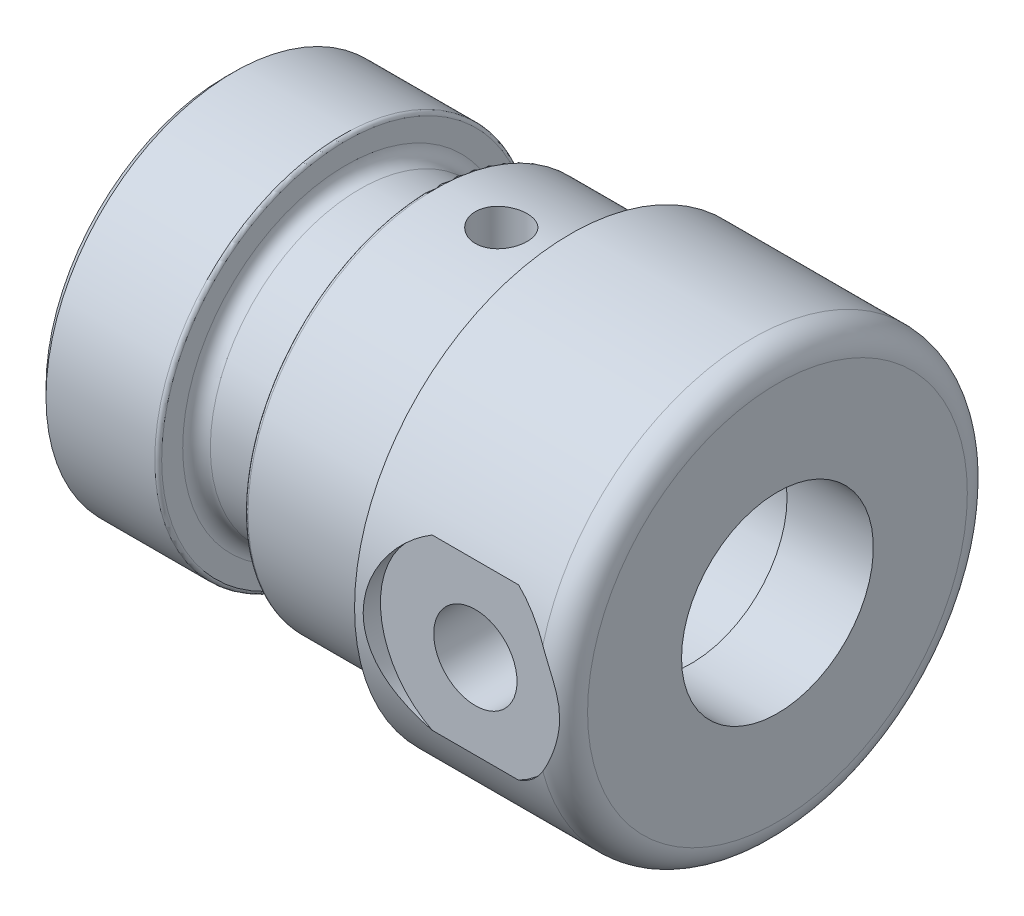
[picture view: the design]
ISO-10303-21;
HEADER;
FILE_DESCRIPTION(('STEP AP214'),'2;1');
FILE_NAME('part.step','',(''),(''),'','','');
FILE_SCHEMA(('AUTOMOTIVE_DESIGN { 1 0 10303 214 1 1 1 1 }'));
ENDSEC;
DATA;
#1=APPLICATION_CONTEXT('core data for automotive mechanical design processes');
#2=APPLICATION_PROTOCOL_DEFINITION('international standard','automotive_design',2000,#1);
#3=PRODUCT_CONTEXT('',#1,'mechanical');
#4=PRODUCT('Part','Part','',(#3));
#5=PRODUCT_RELATED_PRODUCT_CATEGORY('part','',(#4));
#6=PRODUCT_DEFINITION_FORMATION('','',#4);
#7=PRODUCT_DEFINITION_CONTEXT('part definition',#1,'design');
#8=PRODUCT_DEFINITION('design','',#6,#7);
#9=PRODUCT_DEFINITION_SHAPE('','',#8);
#10=(LENGTH_UNIT() NAMED_UNIT(*) SI_UNIT(.MILLI.,.METRE.));
#11=(NAMED_UNIT(*) PLANE_ANGLE_UNIT() SI_UNIT($,.RADIAN.));
#12=(NAMED_UNIT(*) SI_UNIT($,.STERADIAN.) SOLID_ANGLE_UNIT());
#13=UNCERTAINTY_MEASURE_WITH_UNIT(LENGTH_MEASURE(1.E-05),#10,'distance_accuracy_value','');
#14=(GEOMETRIC_REPRESENTATION_CONTEXT(3) GLOBAL_UNCERTAINTY_ASSIGNED_CONTEXT((#13)) GLOBAL_UNIT_ASSIGNED_CONTEXT((#10,
#11,#12)) REPRESENTATION_CONTEXT('',''));
#15=CARTESIAN_POINT('',(0.,0.,0.));
#16=DIRECTION('',(0.,0.,1.));
#17=DIRECTION('',(1.,0.,0.));
#18=AXIS2_PLACEMENT_3D('',#15,#16,#17);
#19=CARTESIAN_POINT('',(0.,0.,0.));
#20=DIRECTION('',(-1.,0.,0.));
#21=DIRECTION('',(0.,0.,1.));
#22=AXIS2_PLACEMENT_3D('',#19,#20,#21);
#23=CYLINDRICAL_SURFACE('',#22,5.55625);
#24=CARTESIAN_POINT('',(32.,0.,0.));
#25=DIRECTION('',(-1.,0.,0.));
#26=DIRECTION('',(0.,0.,1.));
#27=AXIS2_PLACEMENT_3D('',#24,#25,#26);
#28=CIRCLE('',#27,5.55625);
#29=CARTESIAN_POINT('',(32.,0.,5.55624999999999));
#30=VERTEX_POINT('',#29);
#31=EDGE_CURVE('E190',#30,#30,#28,.T.);
#32=ORIENTED_EDGE('',*,*,#31,.F.);
#33=EDGE_LOOP('',(#32));
#34=FACE_BOUND('',#33,.T.);
#35=CARTESIAN_POINT('',(27.0000000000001,0.,0.));
#36=DIRECTION('',(-1.,0.,0.));
#37=DIRECTION('',(0.,0.,1.));
#38=AXIS2_PLACEMENT_3D('',#35,#36,#37);
#39=CIRCLE('',#38,5.55625);
#40=CARTESIAN_POINT('',(27.,-2.19603483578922,5.10385590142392));
#41=VERTEX_POINT('',#40);
#42=CARTESIAN_POINT('',(27.,2.19603483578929,5.10385590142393));
#43=VERTEX_POINT('',#42);
#44=EDGE_CURVE('E109',#41,#43,#39,.F.);
#45=ORIENTED_EDGE('',*,*,#44,.F.);
#46=CARTESIAN_POINT('',(28.4130000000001,0.,5.55625000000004));
#47=CARTESIAN_POINT('',(28.4129937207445,0.128763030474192,5.55624497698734));
#48=CARTESIAN_POINT('',(28.4026322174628,0.257738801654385,5.5517233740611));
#49=CARTESIAN_POINT('',(28.3615871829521,0.511994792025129,5.53408587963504));
#50=CARTESIAN_POINT('',(28.3308532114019,0.637265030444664,5.52094865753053));
#51=CARTESIAN_POINT('',(28.2504225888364,0.880031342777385,5.48747848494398));
#52=CARTESIAN_POINT('',(28.2007923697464,0.997552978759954,5.46717076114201));
#53=CARTESIAN_POINT('',(28.0842672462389,1.22247857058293,5.42131472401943));
#54=CARTESIAN_POINT('',(28.0173767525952,1.32988510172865,5.3957677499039));
#55=CARTESIAN_POINT('',(27.8644530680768,1.53746754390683,5.34043137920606));
#56=CARTESIAN_POINT('',(27.7776425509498,1.63703135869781,5.31049545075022));
#57=CARTESIAN_POINT('',(27.5889907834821,1.82072166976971,5.25035680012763));
#58=CARTESIAN_POINT('',(27.4871410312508,1.90483937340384,5.22015393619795));
#59=CARTESIAN_POINT('',(27.2645849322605,2.05979566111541,5.16104762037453));
#60=CARTESIAN_POINT('',(27.1431533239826,2.12966040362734,5.13230475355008));
#61=CARTESIAN_POINT('',(26.8888396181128,2.24769961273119,5.08172361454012));
#62=CARTESIAN_POINT('',(26.7559639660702,2.29588619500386,5.05988148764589));
#63=CARTESIAN_POINT('',(26.4895779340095,2.36661894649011,5.02717478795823));
#64=CARTESIAN_POINT('',(26.3564459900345,2.3903481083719,5.01580689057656));
#65=CARTESIAN_POINT('',(26.08764245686,2.41517595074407,5.00390342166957));
#66=CARTESIAN_POINT('',(25.9519725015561,2.41628872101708,5.00336110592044));
#67=CARTESIAN_POINT('',(25.6942201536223,2.39673762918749,5.01274790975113));
#68=CARTESIAN_POINT('',(25.571959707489,2.37790912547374,5.02179453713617));
#69=CARTESIAN_POINT('',(25.3325453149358,2.32210861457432,5.04783750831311));
#70=CARTESIAN_POINT('',(25.2153924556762,2.28513276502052,5.06483553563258));
#71=CARTESIAN_POINT('',(24.9864363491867,2.19335626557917,5.10525751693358));
#72=CARTESIAN_POINT('',(24.8748081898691,2.13818029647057,5.12881498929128));
#73=CARTESIAN_POINT('',(24.66193674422,2.01183783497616,5.17967693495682));
#74=CARTESIAN_POINT('',(24.5606977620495,1.94066475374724,5.20698295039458));
#75=CARTESIAN_POINT('',(24.3616140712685,1.77662469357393,5.26533637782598));
#76=CARTESIAN_POINT('',(24.26495098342,1.68235945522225,5.29649614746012));
#77=CARTESIAN_POINT('',(24.0883890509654,1.47867630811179,5.35693096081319));
#78=CARTESIAN_POINT('',(24.0084948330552,1.36925423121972,5.38620548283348));
#79=CARTESIAN_POINT('',(23.8657972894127,1.13450757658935,5.44055960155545));
#80=CARTESIAN_POINT('',(23.8035144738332,1.00883302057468,5.4655043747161));
#81=CARTESIAN_POINT('',(23.7013970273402,0.747428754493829,5.50733486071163));
#82=CARTESIAN_POINT('',(23.6615488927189,0.611705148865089,5.52422542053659));
#83=CARTESIAN_POINT('',(23.6079972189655,0.343895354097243,5.54711464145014));
#84=CARTESIAN_POINT('',(23.592710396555,0.212182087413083,5.55377158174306));
#85=CARTESIAN_POINT('',(23.5839457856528,-0.0520870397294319,5.55757513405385));
#86=CARTESIAN_POINT('',(23.5904610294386,-0.184642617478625,5.55472478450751));
#87=CARTESIAN_POINT('',(23.6240187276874,-0.439154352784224,5.54025525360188));
#88=CARTESIAN_POINT('',(23.6499144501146,-0.561292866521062,5.52912613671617));
#89=CARTESIAN_POINT('',(23.7198626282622,-0.799336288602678,5.49976068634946));
#90=CARTESIAN_POINT('',(23.7639173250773,-0.915240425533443,5.48152347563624));
#91=CARTESIAN_POINT('',(23.8703548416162,-1.14162895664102,5.43895992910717));
#92=CARTESIAN_POINT('',(23.9332673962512,-1.25183079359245,5.41446111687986));
#93=CARTESIAN_POINT('',(24.0750564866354,-1.46051096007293,5.36194173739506));
#94=CARTESIAN_POINT('',(24.1539398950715,-1.55898421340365,5.33391965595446));
#95=CARTESIAN_POINT('',(24.332542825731,-1.74942418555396,5.27466863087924));
#96=CARTESIAN_POINT('',(24.4334012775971,-1.84030042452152,5.24335919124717));
#97=CARTESIAN_POINT('',(24.6493676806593,-2.00418121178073,5.1829353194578));
#98=CARTESIAN_POINT('',(24.7644799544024,-2.0771803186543,5.15382155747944));
#99=CARTESIAN_POINT('',(25.0088419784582,-2.20443007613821,5.10071262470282));
#100=CARTESIAN_POINT('',(25.1383271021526,-2.25827957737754,5.07683059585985));
#101=CARTESIAN_POINT('',(25.4058996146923,-2.34291594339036,5.03833900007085));
#102=CARTESIAN_POINT('',(25.5439789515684,-2.3737240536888,5.0237208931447));
#103=CARTESIAN_POINT('',(25.8126214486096,-2.40920871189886,5.00679323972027));
#104=CARTESIAN_POINT('',(25.9428721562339,-2.41582135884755,5.00357246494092));
#105=CARTESIAN_POINT('',(26.2025732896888,-2.40798643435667,5.00734830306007));
#106=CARTESIAN_POINT('',(26.3320238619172,-2.39354283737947,5.01434298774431));
#107=CARTESIAN_POINT('',(26.5790889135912,-2.34567625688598,5.03689892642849));
#108=CARTESIAN_POINT('',(26.6969630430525,-2.31333865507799,5.05196884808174));
#109=CARTESIAN_POINT('',(26.9256144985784,-2.23171559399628,5.08855076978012));
#110=CARTESIAN_POINT('',(27.0363897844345,-2.18242528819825,5.11006461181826));
#111=CARTESIAN_POINT('',(27.2553056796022,-2.06474617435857,5.15878167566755));
#112=CARTESIAN_POINT('',(27.3628443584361,-1.99535269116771,5.1862572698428));
#113=CARTESIAN_POINT('',(27.5653540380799,-1.84078210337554,5.24311117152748));
#114=CARTESIAN_POINT('',(27.6603200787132,-1.75559880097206,5.27249022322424));
#115=CARTESIAN_POINT('',(27.8430151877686,-1.56359151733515,5.33272975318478));
#116=CARTESIAN_POINT('',(27.9295138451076,-1.4555663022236,5.36351439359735));
#117=CARTESIAN_POINT('',(28.0832591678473,-1.22546498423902,5.42072074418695));
#118=CARTESIAN_POINT('',(28.1504970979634,-1.10338254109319,5.44714047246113));
#119=CARTESIAN_POINT('',(28.2625562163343,-0.849881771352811,5.49234854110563));
#120=CARTESIAN_POINT('',(28.3076675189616,-0.718611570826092,5.51123500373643));
#121=CARTESIAN_POINT('',(28.3579868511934,-0.516991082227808,5.53256145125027));
#122=CARTESIAN_POINT('',(28.3718643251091,-0.449057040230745,5.53850101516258));
#123=CARTESIAN_POINT('',(28.3937338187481,-0.31209363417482,5.547900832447));
#124=CARTESIAN_POINT('',(28.4017300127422,-0.243065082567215,5.55136284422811));
#125=CARTESIAN_POINT('',(28.4088204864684,-0.144894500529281,5.55443594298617));
#126=CARTESIAN_POINT('',(28.4103869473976,-0.115942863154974,5.55511550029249));
#127=CARTESIAN_POINT('',(28.4124774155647,-0.0579977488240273,5.55602309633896));
#128=CARTESIAN_POINT('',(28.4130014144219,-0.0290042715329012,5.55625113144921));
#129=CARTESIAN_POINT('',(28.4130000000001,0.,5.55625000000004));
#130=B_SPLINE_CURVE_WITH_KNOTS('',3,(#46,#47,#48,#49,#50,#51,#52,#53,#54,#55,#56,#57,#58,#59,
#60,#61,#62,#63,#64,#65,#66,#67,#68,#69,#70,#71,#72,#73,#74,#75,#76,#77,#78,#79,#80,#81,#82,#83,
#84,#85,#86,#87,#88,#89,#90,#91,#92,#93,#94,#95,#96,#97,#98,#99,#100,#101,#102,#103,#104,#105,
#106,#107,#108,#109,#110,#111,#112,#113,#114,#115,#116,#117,#118,#119,#120,#121,#122,#123,#124,
#125,#126,#127,#128,#129),.UNSPECIFIED.,.T.,.F.,(4,2,2,2,2,2,2,2,2,2,2,2,2,2,2,2,2,2,2,2,2,2,2,
2,2,2,2,2,2,2,2,2,2,2,2,2,2,2,2,2,2,4),(0.,0.386175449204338,0.773310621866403,1.15909715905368,
1.5447852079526,1.94937007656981,2.3541845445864,2.78106643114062,3.20770944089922,
3.61257996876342,4.0171982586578,4.38756673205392,4.75801365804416,5.13663488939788,
5.5154123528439,5.92925111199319,6.34320390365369,6.7683491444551,7.19323821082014,
7.58944560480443,7.98552638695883,8.35985951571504,8.73423885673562,9.1203176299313,
9.5065628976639,9.92264925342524,10.3388621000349,10.7633411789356,11.1874283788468,
11.5767310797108,11.9659603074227,12.3338231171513,12.7017911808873,13.0928585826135,
13.4840798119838,13.9073542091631,14.3308202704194,14.7485748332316,14.9571043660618,
15.1654857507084,15.2524722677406,15.3394594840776),.UNSPECIFIED.);
#131=EDGE_CURVE('E160',#41,#43,#130,.T.);
#132=ORIENTED_EDGE('',*,*,#131,.T.);
#133=EDGE_LOOP('',(#45,#132));
#134=FACE_BOUND('',#133,.T.);
#135=ADVANCED_FACE('F44',(#34,#134),#23,.F.);
#136=CARTESIAN_POINT('',(0.,0.,0.));
#137=DIRECTION('',(-1.,0.,0.));
#138=DIRECTION('',(0.,0.,1.));
#139=AXIS2_PLACEMENT_3D('',#136,#137,#138);
#140=CYLINDRICAL_SURFACE('',#139,10.875);
#141=CARTESIAN_POINT('',(6.80000000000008,0.,0.));
#142=DIRECTION('',(-1.,0.,0.));
#143=DIRECTION('',(0.,0.,1.));
#144=AXIS2_PLACEMENT_3D('',#141,#142,#143);
#145=CIRCLE('',#144,10.875);
#146=CARTESIAN_POINT('',(6.80000000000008,0.,10.875));
#147=VERTEX_POINT('',#146);
#148=EDGE_CURVE('E258',#147,#147,#145,.T.);
#149=ORIENTED_EDGE('',*,*,#148,.T.);
#150=EDGE_LOOP('',(#149));
#151=FACE_BOUND('',#150,.T.);
#152=CARTESIAN_POINT('',(0.500000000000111,0.,0.));
#153=DIRECTION('',(1.,0.,0.));
#154=DIRECTION('',(0.,0.,-1.));
#155=AXIS2_PLACEMENT_3D('',#152,#153,#154);
#156=CIRCLE('',#155,10.875);
#157=CARTESIAN_POINT('',(0.500000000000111,0.,-10.875));
#158=VERTEX_POINT('',#157);
#159=EDGE_CURVE('E189',#158,#158,#156,.T.);
#160=ORIENTED_EDGE('',*,*,#159,.T.);
#161=EDGE_LOOP('',(#160));
#162=FACE_BOUND('',#161,.T.);
#163=ADVANCED_FACE('F46',(#151,#162),#140,.T.);
#164=CARTESIAN_POINT('',(0.,5.55624999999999,0.));
#165=DIRECTION('',(1.,0.,0.));
#166=DIRECTION('',(0.,0.,-1.));
#167=AXIS2_PLACEMENT_3D('',#164,#165,#166);
#168=PLANE('',#167);
#169=CARTESIAN_POINT('',(0.,0.,0.));
#170=DIRECTION('',(-1.,0.,0.));
#171=DIRECTION('',(0.,0.,1.));
#172=AXIS2_PLACEMENT_3D('',#169,#170,#171);
#173=CIRCLE('',#172,6.);
#174=CARTESIAN_POINT('',(0.,0.,6.00000000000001));
#175=VERTEX_POINT('',#174);
#176=EDGE_CURVE('E113',#175,#175,#173,.T.);
#177=ORIENTED_EDGE('',*,*,#176,.F.);
#178=EDGE_LOOP('',(#177));
#179=FACE_BOUND('',#178,.T.);
#180=CARTESIAN_POINT('',(0.,0.,0.));
#181=DIRECTION('',(1.,0.,0.));
#182=DIRECTION('',(0.,0.,-1.));
#183=AXIS2_PLACEMENT_3D('',#180,#181,#182);
#184=CIRCLE('',#183,10.375);
#185=CARTESIAN_POINT('',(0.,0.,-10.375));
#186=VERTEX_POINT('',#185);
#187=EDGE_CURVE('E187',#186,#186,#184,.F.);
#188=ORIENTED_EDGE('',*,*,#187,.T.);
#189=EDGE_LOOP('',(#188));
#190=FACE_BOUND('',#189,.T.);
#191=ADVANCED_FACE('F173',(#179,#190),#168,.F.);
#192=CARTESIAN_POINT('',(32.,12.5,0.));
#193=DIRECTION('',(-1.,0.,0.));
#194=DIRECTION('',(0.,0.,1.));
#195=AXIS2_PLACEMENT_3D('',#192,#193,#194);
#196=PLANE('',#195);
#197=CARTESIAN_POINT('',(32.,0.,0.));
#198=DIRECTION('',(-1.,0.,0.));
#199=DIRECTION('',(0.,0.,1.));
#200=AXIS2_PLACEMENT_3D('',#197,#198,#199);
#201=CIRCLE('',#200,11.);
#202=CARTESIAN_POINT('',(32.,0.,11.));
#203=VERTEX_POINT('',#202);
#204=EDGE_CURVE('E345',#203,#203,#201,.F.);
#205=ORIENTED_EDGE('',*,*,#204,.T.);
#206=EDGE_LOOP('',(#205));
#207=FACE_BOUND('',#206,.T.);
#208=ORIENTED_EDGE('',*,*,#31,.T.);
#209=EDGE_LOOP('',(#208));
#210=FACE_BOUND('',#209,.T.);
#211=ADVANCED_FACE('F171',(#207,#210),#196,.F.);
#212=CARTESIAN_POINT('',(0.,0.,0.));
#213=DIRECTION('',(-1.,0.,0.));
#214=DIRECTION('',(0.,0.,1.));
#215=AXIS2_PLACEMENT_3D('',#212,#213,#214);
#216=CYLINDRICAL_SURFACE('',#215,12.5);
#217=DIRECTION('',(-1.,0.,0.));
#218=VECTOR('',#217,1.);
#219=CARTESIAN_POINT('',(0.,4.89897948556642,11.5));
#220=LINE('',#219,#218);
#221=CARTESIAN_POINT('',(28.5,4.8989794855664,11.5));
#222=VERTEX_POINT('',#221);
#223=CARTESIAN_POINT('',(23.5,4.89897948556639,11.5));
#224=VERTEX_POINT('',#223);
#225=EDGE_CURVE('E11',#222,#224,#220,.T.);
#226=ORIENTED_EDGE('',*,*,#225,.F.);
#227=CARTESIAN_POINT('',(28.5,4.8989794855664,11.5));
#228=CARTESIAN_POINT('',(28.6410710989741,4.82698356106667,11.5306652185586));
#229=CARTESIAN_POINT('',(28.7786535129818,4.74909801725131,11.5630505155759));
#230=CARTESIAN_POINT('',(29.0461685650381,4.58211025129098,11.6302362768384));
#231=CARTESIAN_POINT('',(29.1761030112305,4.4930106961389,11.6650361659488));
#232=CARTESIAN_POINT('',(29.5535613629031,4.20965109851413,11.7715548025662));
#233=CARTESIAN_POINT('',(29.7886985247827,3.99935156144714,11.8453829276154));
#234=CARTESIAN_POINT('',(30.220047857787,3.54120421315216,11.9903049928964));
#235=CARTESIAN_POINT('',(30.4162636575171,3.29335990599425,12.0613991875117));
#236=CARTESIAN_POINT('',(30.6772407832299,2.89800310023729,12.1601870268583));
#237=CARTESIAN_POINT('',(30.7586944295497,2.76224240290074,12.1918155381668));
#238=CARTESIAN_POINT('',(30.9098543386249,2.48362880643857,12.25160556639));
#239=CARTESIAN_POINT('',(30.9795656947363,2.34077901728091,12.2797685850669));
#240=CARTESIAN_POINT('',(31.1055663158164,2.05127274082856,12.3314054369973));
#241=CARTESIAN_POINT('',(31.1620535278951,1.90471451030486,12.3549474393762));
#242=CARTESIAN_POINT('',(31.2624238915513,1.60673398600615,12.3972187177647));
#243=CARTESIAN_POINT('',(31.3063128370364,1.45531396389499,12.4159502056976));
#244=CARTESIAN_POINT('',(31.3810098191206,1.14874718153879,12.4480572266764));
#245=CARTESIAN_POINT('',(31.4118200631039,0.993601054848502,12.4614336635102));
#246=CARTESIAN_POINT('',(31.4599877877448,0.680852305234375,12.4824274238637));
#247=CARTESIAN_POINT('',(31.4773463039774,0.523249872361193,12.4900451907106));
#248=CARTESIAN_POINT('',(31.497551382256,0.219568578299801,12.4989199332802));
#249=CARTESIAN_POINT('',(31.5014436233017,0.0735716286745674,12.5006351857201));
#250=CARTESIAN_POINT('',(31.4976043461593,-0.218291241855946,12.4989459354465));
#251=CARTESIAN_POINT('',(31.4898689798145,-0.364157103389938,12.495539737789));
#252=CARTESIAN_POINT('',(31.4628604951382,-0.654526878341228,12.483697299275));
#253=CARTESIAN_POINT('',(31.4435936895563,-0.799031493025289,12.4752638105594));
#254=CARTESIAN_POINT('',(31.393729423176,-1.08575702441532,12.4535863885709));
#255=CARTESIAN_POINT('',(31.3631276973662,-1.22797706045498,12.4403406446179));
#256=CARTESIAN_POINT('',(31.2918014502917,-1.50560997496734,12.4097602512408));
#257=CARTESIAN_POINT('',(31.2513465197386,-1.64110420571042,12.3925350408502));
#258=CARTESIAN_POINT('',(31.1603319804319,-1.90811413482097,12.3542435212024));
#259=CARTESIAN_POINT('',(31.1097687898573,-2.03962840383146,12.3331758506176));
#260=CARTESIAN_POINT('',(30.9435171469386,-2.42703027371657,12.2649118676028));
#261=CARTESIAN_POINT('',(30.8132260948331,-2.6759331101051,12.212636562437));
#262=CARTESIAN_POINT('',(30.5086536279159,-3.1638324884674,12.0957442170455));
#263=CARTESIAN_POINT('',(30.3321872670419,-3.40131804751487,12.0305717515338));
#264=CARTESIAN_POINT('',(29.9442517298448,-3.84440880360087,11.896388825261));
#265=CARTESIAN_POINT('',(29.732795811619,-4.05002601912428,11.8273798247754));
#266=CARTESIAN_POINT('',(29.3515425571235,-4.3654866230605,11.713713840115));
#267=CARTESIAN_POINT('',(29.189868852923,-4.48499785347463,11.6682888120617));
#268=CARTESIAN_POINT('',(28.8540056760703,-4.70584437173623,11.5809782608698));
#269=CARTESIAN_POINT('',(28.679833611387,-4.80720427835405,11.5390879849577));
#270=CARTESIAN_POINT('',(28.5,-4.89897948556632,11.5));
#271=B_SPLINE_CURVE_WITH_KNOTS('',3,(#227,#228,#229,#230,#231,#232,#233,#234,#235,#236,#237,
#238,#239,#240,#241,#242,#243,#244,#245,#246,#247,#248,#249,#250,#251,#252,#253,#254,#255,#256,
#257,#258,#259,#260,#261,#262,#263,#264,#265,#266,#267,#268,#269,#270),.UNSPECIFIED.,.F.,.F.,(4,
2,2,2,2,2,2,2,2,2,2,2,2,2,2,2,2,2,2,2,2,4),(0.,0.483637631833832,0.967160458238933,
1.93434797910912,2.90144528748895,3.38527842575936,3.86890115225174,4.34474095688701,
4.82036157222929,5.295901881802,5.77140557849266,6.20903838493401,6.64681605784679,
7.08435429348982,7.52205732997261,7.94891570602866,8.37592560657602,9.22946393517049,
10.1346542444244,11.0395023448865,11.656727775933,12.2731096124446),.UNSPECIFIED.);
#272=CARTESIAN_POINT('',(30.5,3.16227766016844,12.0933866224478));
#273=VERTEX_POINT('',#272);
#274=EDGE_CURVE('E287',#222,#273,#271,.T.);
#275=ORIENTED_EDGE('',*,*,#274,.T.);
#276=CARTESIAN_POINT('',(30.5,0.,0.));
#277=DIRECTION('',(-1.,0.,0.));
#278=DIRECTION('',(0.,0.,1.));
#279=AXIS2_PLACEMENT_3D('',#276,#277,#278);
#280=CIRCLE('',#279,12.5);
#281=CARTESIAN_POINT('',(30.5,-3.16227766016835,12.0933866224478));
#282=VERTEX_POINT('',#281);
#283=EDGE_CURVE('E193',#273,#282,#280,.T.);
#284=ORIENTED_EDGE('',*,*,#283,.T.);
#285=CARTESIAN_POINT('',(28.5,-4.89897948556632,11.5));
#286=VERTEX_POINT('',#285);
#287=EDGE_CURVE('E67',#282,#286,#271,.T.);
#288=ORIENTED_EDGE('',*,*,#287,.T.);
#289=DIRECTION('',(-1.,0.,0.));
#290=VECTOR('',#289,1.);
#291=CARTESIAN_POINT('',(0.,-4.89897948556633,11.5));
#292=LINE('',#291,#290);
#293=CARTESIAN_POINT('',(23.5,-4.8989794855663,11.5));
#294=VERTEX_POINT('',#293);
#295=EDGE_CURVE('E52',#294,#286,#292,.F.);
#296=ORIENTED_EDGE('',*,*,#295,.F.);
#297=CARTESIAN_POINT('',(23.5,-4.8989794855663,11.5));
#298=CARTESIAN_POINT('',(23.358928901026,-4.82698356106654,11.5306652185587));
#299=CARTESIAN_POINT('',(23.2213464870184,-4.74909801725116,11.5630505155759));
#300=CARTESIAN_POINT('',(22.9538314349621,-4.5821102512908,11.6302362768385));
#301=CARTESIAN_POINT('',(22.8238969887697,-4.49301069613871,11.6650361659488));
#302=CARTESIAN_POINT('',(22.446438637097,-4.20965109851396,11.7715548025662));
#303=CARTESIAN_POINT('',(22.2113014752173,-3.99935156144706,11.8453829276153));
#304=CARTESIAN_POINT('',(21.779952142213,-3.54120421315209,11.9903049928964));
#305=CARTESIAN_POINT('',(21.5837363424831,-3.29335990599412,12.0613991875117));
#306=CARTESIAN_POINT('',(21.3227592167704,-2.89800310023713,12.1601870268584));
#307=CARTESIAN_POINT('',(21.2413055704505,-2.76224240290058,12.1918155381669));
#308=CARTESIAN_POINT('',(21.0901456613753,-2.48362880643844,12.2516055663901));
#309=CARTESIAN_POINT('',(21.0204343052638,-2.34077901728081,12.2797685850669));
#310=CARTESIAN_POINT('',(20.8944336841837,-2.05127274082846,12.3314054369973));
#311=CARTESIAN_POINT('',(20.8379464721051,-1.90471451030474,12.3549474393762));
#312=CARTESIAN_POINT('',(20.7375761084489,-1.60673398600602,12.3972187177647));
#313=CARTESIAN_POINT('',(20.6936871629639,-1.45531396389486,12.4159502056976));
#314=CARTESIAN_POINT('',(20.6189901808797,-1.14874718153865,12.4480572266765));
#315=CARTESIAN_POINT('',(20.5881799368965,-0.99360105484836,12.4614336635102));
#316=CARTESIAN_POINT('',(20.5400122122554,-0.680852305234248,12.4824274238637));
#317=CARTESIAN_POINT('',(20.5226536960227,-0.52324987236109,12.4900451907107));
#318=CARTESIAN_POINT('',(20.502448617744,-0.219568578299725,12.4989199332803));
#319=CARTESIAN_POINT('',(20.4985563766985,-0.0735716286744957,12.5006351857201));
#320=CARTESIAN_POINT('',(20.502395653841,0.218291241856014,12.4989459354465));
#321=CARTESIAN_POINT('',(20.5101310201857,0.364157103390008,12.495539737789));
#322=CARTESIAN_POINT('',(20.5371395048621,0.654526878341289,12.483697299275));
#323=CARTESIAN_POINT('',(20.556406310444,0.799031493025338,12.4752638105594));
#324=CARTESIAN_POINT('',(20.6062705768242,1.08575702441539,12.4535863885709));
#325=CARTESIAN_POINT('',(20.6368723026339,1.22797706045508,12.4403406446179));
#326=CARTESIAN_POINT('',(20.7081985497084,1.50560997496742,12.4097602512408));
#327=CARTESIAN_POINT('',(20.7486534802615,1.64110420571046,12.3925350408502));
#328=CARTESIAN_POINT('',(20.8396680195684,1.90811413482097,12.3542435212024));
#329=CARTESIAN_POINT('',(20.890231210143,2.03962840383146,12.3331758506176));
#330=CARTESIAN_POINT('',(21.0564828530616,2.42703027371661,12.2649118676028));
#331=CARTESIAN_POINT('',(21.1867739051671,2.67593311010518,12.2126365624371));
#332=CARTESIAN_POINT('',(21.4913463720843,3.16383248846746,12.0957442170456));
#333=CARTESIAN_POINT('',(21.6678127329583,3.40131804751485,12.0305717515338));
#334=CARTESIAN_POINT('',(22.0557482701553,3.84440880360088,11.896388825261));
#335=CARTESIAN_POINT('',(22.2672041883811,4.05002601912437,11.8273798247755));
#336=CARTESIAN_POINT('',(22.6484574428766,4.36548662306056,11.7137138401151));
#337=CARTESIAN_POINT('',(22.8101311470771,4.48499785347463,11.6682888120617));
#338=CARTESIAN_POINT('',(23.1459943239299,4.70584437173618,11.5809782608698));
#339=CARTESIAN_POINT('',(23.3201663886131,4.80720427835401,11.5390879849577));
#340=CARTESIAN_POINT('',(23.5,4.89897948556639,11.5));
#341=B_SPLINE_CURVE_WITH_KNOTS('',3,(#297,#298,#299,#300,#301,#302,#303,#304,#305,#306,#307,
#308,#309,#310,#311,#312,#313,#314,#315,#316,#317,#318,#319,#320,#321,#322,#323,#324,#325,#326,
#327,#328,#329,#330,#331,#332,#333,#334,#335,#336,#337,#338,#339,#340),.UNSPECIFIED.,.F.,.F.,(4,
2,2,2,2,2,2,2,2,2,2,2,2,2,2,2,2,2,2,2,2,4),(0.,0.483637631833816,0.967160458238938,
1.93434797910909,2.90144528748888,3.38527842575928,3.86890115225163,4.34474095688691,
4.82036157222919,5.29590188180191,5.77140557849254,6.20903838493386,6.64681605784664,
7.08435429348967,7.52205732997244,7.94891570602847,8.37592560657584,9.22946393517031,
10.1346542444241,11.0395023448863,11.6567277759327,12.2731096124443),.UNSPECIFIED.);
#342=EDGE_CURVE('E118',#294,#224,#341,.T.);
#343=ORIENTED_EDGE('',*,*,#342,.T.);
#344=EDGE_LOOP('',(#226,#275,#284,#288,#296,#343));
#345=FACE_BOUND('',#344,.T.);
#346=CARTESIAN_POINT('',(20.0000000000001,0.,0.));
#347=DIRECTION('',(-1.,0.,0.));
#348=DIRECTION('',(0.,0.,1.));
#349=AXIS2_PLACEMENT_3D('',#346,#347,#348);
#350=CIRCLE('',#349,12.5);
#351=CARTESIAN_POINT('',(20.0000000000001,0.,12.5));
#352=VERTEX_POINT('',#351);
#353=EDGE_CURVE('E196',#352,#352,#350,.T.);
#354=ORIENTED_EDGE('',*,*,#353,.F.);
#355=EDGE_LOOP('',(#354));
#356=FACE_BOUND('',#355,.T.);
#357=ADVANCED_FACE('F180',(#345,#356),#216,.T.);
#358=CARTESIAN_POINT('',(20.0000000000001,10.875,0.));
#359=DIRECTION('',(1.,0.,0.));
#360=DIRECTION('',(0.,0.,-1.));
#361=AXIS2_PLACEMENT_3D('',#358,#359,#360);
#362=PLANE('',#361);
#363=CARTESIAN_POINT('',(20.0000000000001,0.,0.));
#364=DIRECTION('',(-1.,0.,0.));
#365=DIRECTION('',(0.,0.,1.));
#366=AXIS2_PLACEMENT_3D('',#363,#364,#365);
#367=CIRCLE('',#366,10.875);
#368=CARTESIAN_POINT('',(20.0000000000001,0.,10.875));
#369=VERTEX_POINT('',#368);
#370=EDGE_CURVE('E207',#369,#369,#367,.T.);
#371=ORIENTED_EDGE('',*,*,#370,.F.);
#372=EDGE_LOOP('',(#371));
#373=FACE_BOUND('',#372,.T.);
#374=ORIENTED_EDGE('',*,*,#353,.T.);
#375=EDGE_LOOP('',(#374));
#376=FACE_BOUND('',#375,.T.);
#377=ADVANCED_FACE('F244',(#373,#376),#362,.F.);
#378=CARTESIAN_POINT('',(0.,0.,0.));
#379=DIRECTION('',(-1.,0.,0.));
#380=DIRECTION('',(0.,0.,1.));
#381=AXIS2_PLACEMENT_3D('',#378,#379,#380);
#382=CYLINDRICAL_SURFACE('',#381,10.875);
#383=CARTESIAN_POINT('',(16.0000000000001,-10.7710549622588,-1.5000000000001));
#384=CARTESIAN_POINT('',(15.9161754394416,-10.7710562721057,-1.49999648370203));
#385=CARTESIAN_POINT('',(15.8323003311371,-10.7720440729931,-1.49294970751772));
#386=CARTESIAN_POINT('',(15.6668897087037,-10.7758864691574,-1.4649531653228));
#387=CARTESIAN_POINT('',(15.5853566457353,-10.7787429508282,-1.44398935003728));
#388=CARTESIAN_POINT('',(15.4270486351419,-10.7859931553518,-1.38879314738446));
#389=CARTESIAN_POINT('',(15.3502702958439,-10.7903857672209,-1.35457034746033));
#390=CARTESIAN_POINT('',(15.2035587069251,-10.8002119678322,-1.27384922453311));
#391=CARTESIAN_POINT('',(15.1336244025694,-10.8056453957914,-1.22735279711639));
#392=CARTESIAN_POINT('',(15.0020988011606,-10.8169822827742,-1.12306679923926));
#393=CARTESIAN_POINT('',(14.9405606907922,-10.8228883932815,-1.06521043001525));
#394=CARTESIAN_POINT('',(14.8280344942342,-10.834481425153,-0.939990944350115));
#395=CARTESIAN_POINT('',(14.7770469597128,-10.840168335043,-0.872627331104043));
#396=CARTESIAN_POINT('',(14.6868755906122,-10.8507096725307,-0.729967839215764));
#397=CARTESIAN_POINT('',(14.6477403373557,-10.8555606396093,-0.654640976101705));
#398=CARTESIAN_POINT('',(14.5826958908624,-10.863854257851,-0.498405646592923));
#399=CARTESIAN_POINT('',(14.5567861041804,-10.867296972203,-0.417497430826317));
#400=CARTESIAN_POINT('',(14.5190882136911,-10.8723674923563,-0.252942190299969));
#401=CARTESIAN_POINT('',(14.5072113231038,-10.8740067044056,-0.169315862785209));
#402=CARTESIAN_POINT('',(14.4976409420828,-10.8753245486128,-0.00124218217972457));
#403=CARTESIAN_POINT('',(14.4999467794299,-10.8750032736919,0.0832051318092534));
#404=CARTESIAN_POINT('',(14.5186057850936,-10.872445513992,0.249918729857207));
#405=CARTESIAN_POINT('',(14.5348634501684,-10.8702220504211,0.332195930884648));
#406=CARTESIAN_POINT('',(14.5808150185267,-10.8641242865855,0.492843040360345));
#407=CARTESIAN_POINT('',(14.6105092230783,-10.8602499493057,0.571212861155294));
#408=CARTESIAN_POINT('',(14.6825906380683,-10.8512633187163,0.72211297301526));
#409=CARTESIAN_POINT('',(14.7250186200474,-10.8461470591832,0.794623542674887));
#410=CARTESIAN_POINT('',(14.821333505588,-10.835247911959,0.931531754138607));
#411=CARTESIAN_POINT('',(14.8752210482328,-10.8294649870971,0.995928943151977));
#412=CARTESIAN_POINT('',(14.9934588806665,-10.817821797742,1.11534442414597));
#413=CARTESIAN_POINT('',(15.0578924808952,-10.8119612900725,1.17028023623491));
#414=CARTESIAN_POINT('',(15.1951087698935,-10.8008706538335,1.26857100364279));
#415=CARTESIAN_POINT('',(15.2678914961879,-10.7956405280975,1.31192590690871));
#416=CARTESIAN_POINT('',(15.4198196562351,-10.7864029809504,1.38583204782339));
#417=CARTESIAN_POINT('',(15.4989687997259,-10.7823962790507,1.41637575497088));
#418=CARTESIAN_POINT('',(15.6613406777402,-10.7760725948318,1.46371449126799));
#419=CARTESIAN_POINT('',(15.7445631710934,-10.7737555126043,1.48051033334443));
#420=CARTESIAN_POINT('',(15.9119882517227,-10.7710920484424,1.49976541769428));
#421=CARTESIAN_POINT('',(15.9961771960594,-10.7707296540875,1.50234115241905));
#422=CARTESIAN_POINT('',(16.1637854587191,-10.771974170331,1.49339113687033));
#423=CARTESIAN_POINT('',(16.2472047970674,-10.7735810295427,1.4818657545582));
#424=CARTESIAN_POINT('',(16.410550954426,-10.7785683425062,1.44513911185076));
#425=CARTESIAN_POINT('',(16.4904908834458,-10.7819413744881,1.41999506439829));
#426=CARTESIAN_POINT('',(16.6450207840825,-10.7900749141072,1.35680403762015));
#427=CARTESIAN_POINT('',(16.7196105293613,-10.7948354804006,1.31875651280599));
#428=CARTESIAN_POINT('',(16.8618473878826,-10.8052457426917,1.23055538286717));
#429=CARTESIAN_POINT('',(16.9294470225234,-10.8109009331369,1.18032587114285));
#430=CARTESIAN_POINT('',(17.0552985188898,-10.8224463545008,1.06929301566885));
#431=CARTESIAN_POINT('',(17.1135499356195,-10.8283365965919,1.00848916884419));
#432=CARTESIAN_POINT('',(17.2194651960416,-10.8397380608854,0.877522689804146));
#433=CARTESIAN_POINT('',(17.2670521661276,-10.8452463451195,0.807297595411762));
#434=CARTESIAN_POINT('',(17.3497539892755,-10.8552184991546,0.659783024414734));
#435=CARTESIAN_POINT('',(17.3848691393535,-10.8596823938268,0.582493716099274));
#436=CARTESIAN_POINT('',(17.4415056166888,-10.8670498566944,0.423292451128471));
#437=CARTESIAN_POINT('',(17.4630701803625,-10.8699583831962,0.341396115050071));
#438=CARTESIAN_POINT('',(17.4921336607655,-10.873908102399,0.17510195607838));
#439=CARTESIAN_POINT('',(17.499633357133,-10.8749493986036,0.0907042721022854));
#440=CARTESIAN_POINT('',(17.5003374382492,-10.8750465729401,-0.077448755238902));
#441=CARTESIAN_POINT('',(17.4936598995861,-10.8741188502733,-0.161203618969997));
#442=CARTESIAN_POINT('',(17.4664506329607,-10.870415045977,-0.326388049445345));
#443=CARTESIAN_POINT('',(17.4459189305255,-10.8676389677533,-0.407817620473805));
#444=CARTESIAN_POINT('',(17.3916236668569,-10.8605488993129,-0.566016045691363));
#445=CARTESIAN_POINT('',(17.3578670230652,-10.8562357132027,-0.642787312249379));
#446=CARTESIAN_POINT('',(17.2780924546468,-10.846547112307,-0.789594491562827));
#447=CARTESIAN_POINT('',(17.2320742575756,-10.8411716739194,-0.859630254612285));
#448=CARTESIAN_POINT('',(17.128650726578,-10.8299040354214,-0.99157961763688));
#449=CARTESIAN_POINT('',(17.0711578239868,-10.8240080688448,-1.05342426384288));
#450=CARTESIAN_POINT('',(16.9466005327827,-10.8123929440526,-1.1666323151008));
#451=CARTESIAN_POINT('',(16.8795338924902,-10.806673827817,-1.21799324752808));
#452=CARTESIAN_POINT('',(16.7373651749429,-10.7960311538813,-1.30898866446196));
#453=CARTESIAN_POINT('',(16.662226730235,-10.7911114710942,-1.34856676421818));
#454=CARTESIAN_POINT('',(16.506340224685,-10.7826700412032,-1.41448432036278));
#455=CARTESIAN_POINT('',(16.4255982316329,-10.7791468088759,-1.44083784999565));
#456=CARTESIAN_POINT('',(16.2870539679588,-10.7747322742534,-1.47341045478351));
#457=CARTESIAN_POINT('',(16.2301170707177,-10.7733603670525,-1.48336674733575));
#458=CARTESIAN_POINT('',(16.1154614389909,-10.7715212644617,-1.49666269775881));
#459=CARTESIAN_POINT('',(16.0577427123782,-10.7710540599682,-1.50000242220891));
#460=CARTESIAN_POINT('',(16.0000000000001,-10.7710549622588,-1.5000000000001));
#461=B_SPLINE_CURVE_WITH_KNOTS('',3,(#383,#384,#385,#386,#387,#388,#389,#390,#391,#392,#393,
#394,#395,#396,#397,#398,#399,#400,#401,#402,#403,#404,#405,#406,#407,#408,#409,#410,#411,#412,
#413,#414,#415,#416,#417,#418,#419,#420,#421,#422,#423,#424,#425,#426,#427,#428,#429,#430,#431,
#432,#433,#434,#435,#436,#437,#438,#439,#440,#441,#442,#443,#444,#445,#446,#447,#448,#449,#450,
#451,#452,#453,#454,#455,#456,#457,#458,#459,#460),.UNSPECIFIED.,.T.,.F.,(4,2,2,2,2,2,2,2,2,2,2,
2,2,2,2,2,2,2,2,2,2,2,2,2,2,2,2,2,2,2,2,2,2,2,2,2,2,2,4),(0.,0.251262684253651,
0.502779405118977,0.754114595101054,1.00541099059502,1.2582318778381,1.51106598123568,
1.76492282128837,2.01876826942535,2.27099887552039,2.52321752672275,2.7737233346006,
3.02423475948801,3.27555699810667,3.52689325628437,3.78032038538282,4.03374865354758,
4.28732568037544,4.54088771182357,4.7923694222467,5.04384457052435,5.29427135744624,
5.54470873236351,5.79674860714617,6.04880047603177,6.30261463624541,6.55642275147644,
6.80941686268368,7.06239694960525,7.31327833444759,7.56415925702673,7.8149091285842,
8.06566457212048,8.31841233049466,8.57121963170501,8.82521794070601,9.07894537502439,
9.2520299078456,9.42511269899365),.UNSPECIFIED.);
#462=CARTESIAN_POINT('',(16.0000000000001,-10.7710549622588,-1.5000000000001));
#463=VERTEX_POINT('',#462);
#464=EDGE_CURVE('E115',#463,#463,#461,.T.);
#465=ORIENTED_EDGE('',*,*,#464,.T.);
#466=EDGE_LOOP('',(#465));
#467=FACE_BOUND('',#466,.T.);
#468=CARTESIAN_POINT('',(12.2,0.,0.));
#469=DIRECTION('',(1.,0.,0.));
#470=DIRECTION('',(0.,0.,-1.));
#471=AXIS2_PLACEMENT_3D('',#468,#469,#470);
#472=CIRCLE('',#471,10.875);
#473=CARTESIAN_POINT('',(12.2,0.,-10.875));
#474=VERTEX_POINT('',#473);
#475=EDGE_CURVE('E271',#474,#474,#472,.T.);
#476=ORIENTED_EDGE('',*,*,#475,.T.);
#477=EDGE_LOOP('',(#476));
#478=FACE_BOUND('',#477,.T.);
#479=CARTESIAN_POINT('',(16.0000000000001,10.7710549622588,1.50000000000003));
#480=CARTESIAN_POINT('',(15.9161754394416,10.7710562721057,1.49999648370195));
#481=CARTESIAN_POINT('',(15.8323003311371,10.7720440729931,1.49294970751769));
#482=CARTESIAN_POINT('',(15.6668897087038,10.7758864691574,1.46495316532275));
#483=CARTESIAN_POINT('',(15.5853566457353,10.7787429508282,1.44398935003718));
#484=CARTESIAN_POINT('',(15.427048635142,10.7859931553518,1.38879314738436));
#485=CARTESIAN_POINT('',(15.3502702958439,10.7903857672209,1.35457034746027));
#486=CARTESIAN_POINT('',(15.2035587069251,10.8002119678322,1.27384922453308));
#487=CARTESIAN_POINT('',(15.1336244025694,10.8056453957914,1.22735279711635));
#488=CARTESIAN_POINT('',(15.0020988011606,10.8169822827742,1.12306679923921));
#489=CARTESIAN_POINT('',(14.9405606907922,10.8228883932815,1.0652104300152));
#490=CARTESIAN_POINT('',(14.8280344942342,10.834481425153,0.939990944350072));
#491=CARTESIAN_POINT('',(14.7770469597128,10.8401683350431,0.872627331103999));
#492=CARTESIAN_POINT('',(14.6868755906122,10.8507096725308,0.729967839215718));
#493=CARTESIAN_POINT('',(14.6477403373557,10.8555606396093,0.654640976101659));
#494=CARTESIAN_POINT('',(14.5826958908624,10.863854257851,0.498405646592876));
#495=CARTESIAN_POINT('',(14.5567861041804,10.867296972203,0.417497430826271));
#496=CARTESIAN_POINT('',(14.5190882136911,10.8723674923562,0.25294219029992));
#497=CARTESIAN_POINT('',(14.5072113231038,10.8740067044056,0.169315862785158));
#498=CARTESIAN_POINT('',(14.4976409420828,10.8753245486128,0.00124218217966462));
#499=CARTESIAN_POINT('',(14.4999467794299,10.8750032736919,-0.0832051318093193));
#500=CARTESIAN_POINT('',(14.5186057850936,10.872445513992,-0.249918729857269));
#501=CARTESIAN_POINT('',(14.5348634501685,10.8702220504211,-0.332195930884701));
#502=CARTESIAN_POINT('',(14.5808150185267,10.8641242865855,-0.4928430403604));
#503=CARTESIAN_POINT('',(14.6105092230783,10.8602499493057,-0.57121286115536));
#504=CARTESIAN_POINT('',(14.6825906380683,10.8512633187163,-0.722112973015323));
#505=CARTESIAN_POINT('',(14.7250186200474,10.8461470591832,-0.794623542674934));
#506=CARTESIAN_POINT('',(14.821333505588,10.835247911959,-0.931531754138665));
#507=CARTESIAN_POINT('',(14.8752210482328,10.8294649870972,-0.995928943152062));
#508=CARTESIAN_POINT('',(14.9934588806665,10.8178217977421,-1.11534442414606));
#509=CARTESIAN_POINT('',(15.0578924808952,10.8119612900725,-1.17028023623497));
#510=CARTESIAN_POINT('',(15.1951087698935,10.8008706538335,-1.26857100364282));
#511=CARTESIAN_POINT('',(15.2678914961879,10.7956405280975,-1.31192590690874));
#512=CARTESIAN_POINT('',(15.419819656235,10.7864029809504,-1.38583204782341));
#513=CARTESIAN_POINT('',(15.4989687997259,10.7823962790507,-1.4163757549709));
#514=CARTESIAN_POINT('',(15.6613406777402,10.7760725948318,-1.46371449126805));
#515=CARTESIAN_POINT('',(15.7445631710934,10.7737555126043,-1.48051033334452));
#516=CARTESIAN_POINT('',(15.9119882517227,10.7710920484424,-1.49976541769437));
#517=CARTESIAN_POINT('',(15.9961771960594,10.7707296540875,-1.50234115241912));
#518=CARTESIAN_POINT('',(16.1637854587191,10.771974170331,-1.49339113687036));
#519=CARTESIAN_POINT('',(16.2472047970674,10.7735810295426,-1.48186575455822));
#520=CARTESIAN_POINT('',(16.410550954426,10.7785683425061,-1.44513911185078));
#521=CARTESIAN_POINT('',(16.4904908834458,10.781941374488,-1.41999506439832));
#522=CARTESIAN_POINT('',(16.6450207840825,10.7900749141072,-1.35680403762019));
#523=CARTESIAN_POINT('',(16.7196105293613,10.7948354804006,-1.31875651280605));
#524=CARTESIAN_POINT('',(16.8618473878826,10.8052457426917,-1.23055538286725));
#525=CARTESIAN_POINT('',(16.9294470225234,10.8109009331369,-1.18032587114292));
#526=CARTESIAN_POINT('',(17.0552985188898,10.8224463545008,-1.0692930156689));
#527=CARTESIAN_POINT('',(17.1135499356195,10.8283365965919,-1.00848916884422));
#528=CARTESIAN_POINT('',(17.2194651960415,10.8397380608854,-0.877522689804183));
#529=CARTESIAN_POINT('',(17.2670521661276,10.8452463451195,-0.807297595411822));
#530=CARTESIAN_POINT('',(17.3497539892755,10.8552184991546,-0.659783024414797));
#531=CARTESIAN_POINT('',(17.3848691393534,10.8596823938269,-0.582493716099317));
#532=CARTESIAN_POINT('',(17.4415056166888,10.8670498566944,-0.423292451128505));
#533=CARTESIAN_POINT('',(17.4630701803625,10.8699583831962,-0.341396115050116));
#534=CARTESIAN_POINT('',(17.4921336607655,10.873908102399,-0.17510195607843));
#535=CARTESIAN_POINT('',(17.499633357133,10.8749493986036,-0.0907042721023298));
#536=CARTESIAN_POINT('',(17.5003374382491,10.8750465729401,0.0774487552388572));
#537=CARTESIAN_POINT('',(17.4936598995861,10.8741188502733,0.161203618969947));
#538=CARTESIAN_POINT('',(17.4664506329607,10.870415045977,0.326388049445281));
#539=CARTESIAN_POINT('',(17.4459189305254,10.8676389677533,0.407817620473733));
#540=CARTESIAN_POINT('',(17.3916236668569,10.8605488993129,0.56601604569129));
#541=CARTESIAN_POINT('',(17.3578670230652,10.8562357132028,0.64278731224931));
#542=CARTESIAN_POINT('',(17.2780924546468,10.846547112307,0.789594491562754));
#543=CARTESIAN_POINT('',(17.2320742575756,10.8411716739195,0.859630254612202));
#544=CARTESIAN_POINT('',(17.128650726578,10.8299040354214,0.991579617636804));
#545=CARTESIAN_POINT('',(17.0711578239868,10.8240080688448,1.05342426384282));
#546=CARTESIAN_POINT('',(16.9466005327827,10.8123929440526,1.16663231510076));
#547=CARTESIAN_POINT('',(16.8795338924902,10.806673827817,1.21799324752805));
#548=CARTESIAN_POINT('',(16.7373651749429,10.7960311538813,1.30898866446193));
#549=CARTESIAN_POINT('',(16.662226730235,10.7911114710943,1.34856676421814));
#550=CARTESIAN_POINT('',(16.506340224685,10.7826700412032,1.41448432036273));
#551=CARTESIAN_POINT('',(16.4255982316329,10.7791468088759,1.4408378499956));
#552=CARTESIAN_POINT('',(16.2870539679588,10.7747322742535,1.47341045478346));
#553=CARTESIAN_POINT('',(16.2301170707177,10.7733603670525,1.48336674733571));
#554=CARTESIAN_POINT('',(16.1154614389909,10.7715212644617,1.49666269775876));
#555=CARTESIAN_POINT('',(16.0577427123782,10.7710540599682,1.50000242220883));
#556=CARTESIAN_POINT('',(16.0000000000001,10.7710549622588,1.50000000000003));
#557=B_SPLINE_CURVE_WITH_KNOTS('',3,(#479,#480,#481,#482,#483,#484,#485,#486,#487,#488,#489,
#490,#491,#492,#493,#494,#495,#496,#497,#498,#499,#500,#501,#502,#503,#504,#505,#506,#507,#508,
#509,#510,#511,#512,#513,#514,#515,#516,#517,#518,#519,#520,#521,#522,#523,#524,#525,#526,#527,
#528,#529,#530,#531,#532,#533,#534,#535,#536,#537,#538,#539,#540,#541,#542,#543,#544,#545,#546,
#547,#548,#549,#550,#551,#552,#553,#554,#555,#556),.UNSPECIFIED.,.T.,.F.,(4,2,2,2,2,2,2,2,2,2,2,
2,2,2,2,2,2,2,2,2,2,2,2,2,2,2,2,2,2,2,2,2,2,2,2,2,2,2,4),(0.,0.251262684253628,
0.502779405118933,0.754114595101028,1.00541099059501,1.25823187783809,1.51106598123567,
1.76492282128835,2.01876826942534,2.27099887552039,2.52321752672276,2.7737233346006,
3.02423475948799,3.27555699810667,3.5268932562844,3.78032038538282,4.03374865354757,
4.28732568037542,4.54088771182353,4.79236942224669,5.04384457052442,5.29427135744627,
5.5447087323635,5.79674860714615,6.04880047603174,6.30261463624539,6.55642275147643,
6.80941686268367,7.06239694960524,7.31327833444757,7.56415925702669,7.81490912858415,
8.06566457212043,8.31841233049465,8.571219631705,8.82521794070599,9.07894537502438,
9.25202990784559,9.42511269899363),.UNSPECIFIED.);
#558=CARTESIAN_POINT('',(16.0000000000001,10.7710549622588,1.50000000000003));
#559=VERTEX_POINT('',#558);
#560=EDGE_CURVE('E200',#559,#559,#557,.T.);
#561=ORIENTED_EDGE('',*,*,#560,.T.);
#562=EDGE_LOOP('',(#561));
#563=FACE_BOUND('',#562,.T.);
#564=ORIENTED_EDGE('',*,*,#370,.T.);
#565=EDGE_LOOP('',(#564));
#566=FACE_BOUND('',#565,.T.);
#567=ADVANCED_FACE('F210',(#467,#478,#563,#566),#382,.T.);
#568=CARTESIAN_POINT('',(12.0000000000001,8.65499999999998,0.));
#569=DIRECTION('',(1.,0.,0.));
#570=DIRECTION('',(0.,0.,-1.));
#571=AXIS2_PLACEMENT_3D('',#568,#569,#570);
#572=PLANE('',#571);
#573=CARTESIAN_POINT('',(12.0000000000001,0.,0.));
#574=DIRECTION('',(1.,0.,0.));
#575=DIRECTION('',(0.,0.,-1.));
#576=AXIS2_PLACEMENT_3D('',#573,#574,#575);
#577=CIRCLE('',#576,10.675);
#578=CARTESIAN_POINT('',(12.0000000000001,0.,-10.675));
#579=VERTEX_POINT('',#578);
#580=EDGE_CURVE('E249',#579,#579,#577,.F.);
#581=ORIENTED_EDGE('',*,*,#580,.T.);
#582=EDGE_LOOP('',(#581));
#583=FACE_BOUND('',#582,.T.);
#584=CARTESIAN_POINT('',(12.0000000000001,0.,0.));
#585=DIRECTION('',(1.,0.,0.));
#586=DIRECTION('',(0.,0.,-1.));
#587=AXIS2_PLACEMENT_3D('',#584,#585,#586);
#588=CIRCLE('',#587,9.455);
#589=CARTESIAN_POINT('',(12.0000000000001,0.,-9.45499999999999));
#590=VERTEX_POINT('',#589);
#591=EDGE_CURVE('E252',#590,#590,#588,.T.);
#592=ORIENTED_EDGE('',*,*,#591,.T.);
#593=EDGE_LOOP('',(#592));
#594=FACE_BOUND('',#593,.T.);
#595=ADVANCED_FACE('F237',(#583,#594),#572,.F.);
#596=CARTESIAN_POINT('',(0.,0.,0.));
#597=DIRECTION('',(-1.,0.,0.));
#598=DIRECTION('',(0.,0.,1.));
#599=AXIS2_PLACEMENT_3D('',#596,#597,#598);
#600=CYLINDRICAL_SURFACE('',#599,8.655);
#601=CARTESIAN_POINT('',(11.2,0.,0.));
#602=DIRECTION('',(1.,0.,0.));
#603=DIRECTION('',(0.,0.,-1.));
#604=AXIS2_PLACEMENT_3D('',#601,#602,#603);
#605=CIRCLE('',#604,8.655);
#606=CARTESIAN_POINT('',(11.2,0.,-8.65499999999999));
#607=VERTEX_POINT('',#606);
#608=EDGE_CURVE('E255',#607,#607,#605,.F.);
#609=ORIENTED_EDGE('',*,*,#608,.T.);
#610=EDGE_LOOP('',(#609));
#611=FACE_BOUND('',#610,.T.);
#612=CARTESIAN_POINT('',(7.80000000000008,0.,0.));
#613=DIRECTION('',(-1.,0.,0.));
#614=DIRECTION('',(0.,0.,1.));
#615=AXIS2_PLACEMENT_3D('',#612,#613,#614);
#616=CIRCLE('',#615,8.655);
#617=CARTESIAN_POINT('',(7.80000000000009,0.,8.655));
#618=VERTEX_POINT('',#617);
#619=EDGE_CURVE('E261',#618,#618,#616,.F.);
#620=ORIENTED_EDGE('',*,*,#619,.T.);
#621=EDGE_LOOP('',(#620));
#622=FACE_BOUND('',#621,.T.);
#623=ADVANCED_FACE('F234',(#611,#622),#600,.T.);
#624=CARTESIAN_POINT('',(7.00000000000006,10.875,0.));
#625=DIRECTION('',(-1.,0.,0.));
#626=DIRECTION('',(0.,0.,1.));
#627=AXIS2_PLACEMENT_3D('',#624,#625,#626);
#628=PLANE('',#627);
#629=CARTESIAN_POINT('',(7.00000000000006,0.,0.));
#630=DIRECTION('',(-1.,0.,0.));
#631=DIRECTION('',(0.,0.,1.));
#632=AXIS2_PLACEMENT_3D('',#629,#630,#631);
#633=CIRCLE('',#632,10.675);
#634=CARTESIAN_POINT('',(7.00000000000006,0.,10.675));
#635=VERTEX_POINT('',#634);
#636=EDGE_CURVE('E267',#635,#635,#633,.F.);
#637=ORIENTED_EDGE('',*,*,#636,.T.);
#638=EDGE_LOOP('',(#637));
#639=FACE_BOUND('',#638,.T.);
#640=CARTESIAN_POINT('',(7.00000000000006,0.,0.));
#641=DIRECTION('',(-1.,0.,0.));
#642=DIRECTION('',(0.,0.,1.));
#643=AXIS2_PLACEMENT_3D('',#640,#641,#642);
#644=CIRCLE('',#643,9.455);
#645=CARTESIAN_POINT('',(7.00000000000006,0.,9.45500000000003));
#646=VERTEX_POINT('',#645);
#647=EDGE_CURVE('E254',#646,#646,#644,.T.);
#648=ORIENTED_EDGE('',*,*,#647,.T.);
#649=EDGE_LOOP('',(#648));
#650=FACE_BOUND('',#649,.T.);
#651=ADVANCED_FACE('F230',(#639,#650),#628,.F.);
#652=CARTESIAN_POINT('',(0.,0.,0.));
#653=DIRECTION('',(1.,0.,0.));
#654=DIRECTION('',(0.,0.,-1.));
#655=AXIS2_PLACEMENT_3D('',#652,#653,#654);
#656=CONICAL_SURFACE('',#655,10.375,0.785398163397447);
#657=ORIENTED_EDGE('',*,*,#159,.F.);
#658=EDGE_LOOP('',(#657));
#659=FACE_BOUND('',#658,.T.);
#660=ORIENTED_EDGE('',*,*,#187,.F.);
#661=EDGE_LOOP('',(#660));
#662=FACE_BOUND('',#661,.T.);
#663=ADVANCED_FACE('F220',(#659,#662),#656,.T.);
#664=CARTESIAN_POINT('',(16.0000000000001,11.125,0.));
#665=DIRECTION('',(0.,1.,0.));
#666=DIRECTION('',(0.,0.,1.));
#667=AXIS2_PLACEMENT_3D('',#664,#665,#666);
#668=CYLINDRICAL_SURFACE('',#667,1.49999999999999);
#669=CARTESIAN_POINT('',(16.0000000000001,7.125,0.));
#670=DIRECTION('',(0.,1.,0.));
#671=DIRECTION('',(0.,0.,1.));
#672=AXIS2_PLACEMENT_3D('',#669,#670,#671);
#673=CIRCLE('',#672,1.5);
#674=CARTESIAN_POINT('',(16.0000000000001,7.125,1.50000000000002));
#675=VERTEX_POINT('',#674);
#676=EDGE_CURVE('E208',#675,#675,#673,.T.);
#677=ORIENTED_EDGE('',*,*,#676,.F.);
#678=EDGE_LOOP('',(#677));
#679=FACE_BOUND('',#678,.T.);
#680=ORIENTED_EDGE('',*,*,#560,.F.);
#681=EDGE_LOOP('',(#680));
#682=FACE_BOUND('',#681,.T.);
#683=ADVANCED_FACE('F214',(#679,#682),#668,.F.);
#684=CARTESIAN_POINT('',(16.0000000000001,7.125,0.));
#685=DIRECTION('',(0.,1.,0.));
#686=DIRECTION('',(0.,0.,1.));
#687=AXIS2_PLACEMENT_3D('',#684,#685,#686);
#688=CONICAL_SURFACE('',#687,1.5,1.02974425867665);
#689=CARTESIAN_POINT('',(16.0000000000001,6.22370907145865,0.));
#690=VERTEX_POINT('',#689);
#691=VERTEX_LOOP('',#690);
#692=FACE_BOUND('',#691,.T.);
#693=ORIENTED_EDGE('',*,*,#676,.T.);
#694=EDGE_LOOP('',(#693));
#695=FACE_BOUND('',#694,.T.);
#696=ADVANCED_FACE('F219',(#692,#695),#688,.F.);
#697=CARTESIAN_POINT('',(30.5,0.,0.));
#698=DIRECTION('',(-1.,0.,0.));
#699=DIRECTION('',(0.,0.,1.));
#700=AXIS2_PLACEMENT_3D('',#697,#698,#699);
#701=TOROIDAL_SURFACE('',#700,11.,1.5);
#702=CARTESIAN_POINT('',(30.4998,-3.16256224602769,12.0933121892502));
#703=CARTESIAN_POINT('',(30.5587247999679,-3.07876657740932,12.1152380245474));
#704=CARTESIAN_POINT('',(30.6157033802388,-2.99267583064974,12.1332406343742));
#705=CARTESIAN_POINT('',(30.7251093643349,-2.81673184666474,12.1624394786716));
#706=CARTESIAN_POINT('',(30.7775443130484,-2.72688522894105,12.1736471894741));
#707=CARTESIAN_POINT('',(30.8771038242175,-2.54452534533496,12.190312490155));
#708=CARTESIAN_POINT('',(30.9242587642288,-2.45203163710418,12.1958046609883));
#709=CARTESIAN_POINT('',(31.0133283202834,-2.26436136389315,12.2022372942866));
#710=CARTESIAN_POINT('',(31.0552401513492,-2.16918340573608,12.2031753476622));
#711=CARTESIAN_POINT('',(31.1512816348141,-1.93314661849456,12.2012239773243));
#712=CARTESIAN_POINT('',(31.2023831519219,-1.79106615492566,12.1964151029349));
#713=CARTESIAN_POINT('',(31.2927036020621,-1.50334639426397,12.1829092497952));
#714=CARTESIAN_POINT('',(31.3319177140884,-1.35770567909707,12.1742106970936));
#715=CARTESIAN_POINT('',(31.3982946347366,-1.06356319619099,12.1563981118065));
#716=CARTESIAN_POINT('',(31.4254446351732,-0.915058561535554,12.1472836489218));
#717=CARTESIAN_POINT('',(31.4674528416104,-0.61621037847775,12.1319082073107));
#718=CARTESIAN_POINT('',(31.4823153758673,-0.465867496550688,12.1256462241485));
#719=CARTESIAN_POINT('',(31.4996957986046,-0.16296656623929,12.1182282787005));
#720=CARTESIAN_POINT('',(31.5021013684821,-0.0104007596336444,12.1171187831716));
#721=CARTESIAN_POINT('',(31.4942328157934,0.294362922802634,12.1205592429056));
#722=CARTESIAN_POINT('',(31.4839560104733,0.446560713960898,12.1251103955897));
#723=CARTESIAN_POINT('',(31.4508030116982,0.749702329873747,12.13816863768));
#724=CARTESIAN_POINT('',(31.4279005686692,0.900642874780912,12.1466839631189));
#725=CARTESIAN_POINT('',(31.3696530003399,1.2000324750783,12.1645605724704));
#726=CARTESIAN_POINT('',(31.3343097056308,1.34848189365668,12.1739217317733));
#727=CARTESIAN_POINT('',(31.2596370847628,1.6128040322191,12.1883202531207));
#728=CARTESIAN_POINT('',(31.2225054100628,1.72927371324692,12.1938474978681));
#729=CARTESIAN_POINT('',(31.1405251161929,1.9595741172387,12.2013089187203));
#730=CARTESIAN_POINT('',(31.0956785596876,2.07340553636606,12.2032440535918));
#731=CARTESIAN_POINT('',(30.9987361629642,2.29726852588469,12.2017257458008));
#732=CARTESIAN_POINT('',(30.9466764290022,2.40731581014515,12.1982983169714));
#733=CARTESIAN_POINT('',(30.8355872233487,2.62332210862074,12.1843640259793));
#734=CARTESIAN_POINT('',(30.7765632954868,2.72928428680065,12.1738627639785));
#735=CARTESIAN_POINT('',(30.6804374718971,2.8892669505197,12.1508471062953));
#736=CARTESIAN_POINT('',(30.6455252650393,2.94506127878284,12.1414025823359));
#737=CARTESIAN_POINT('',(30.5739341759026,3.05506935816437,12.1196073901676));
#738=CARTESIAN_POINT('',(30.5372521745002,3.10928002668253,12.1072514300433));
#739=CARTESIAN_POINT('',(30.4998,3.16256224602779,12.0933121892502));
#740=B_SPLINE_CURVE_WITH_KNOTS('',3,(#702,#703,#704,#705,#706,#707,#708,#709,#710,#711,#712,
#713,#714,#715,#716,#717,#718,#719,#720,#721,#722,#723,#724,#725,#726,#727,#728,#729,#730,#731,
#732,#733,#734,#735,#736,#737,#738,#739),.UNSPECIFIED.,.F.,.F.,(4,2,2,2,2,2,2,2,2,2,2,2,2,2,2,2,
2,2,4),(0.,0.3140484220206,0.627564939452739,0.939173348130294,1.25094657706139,
1.70349345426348,2.15622361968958,2.60943329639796,3.06248326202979,3.51961114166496,
3.97683573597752,4.43501453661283,4.89312594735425,5.25995140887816,5.62667894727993,
5.99163299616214,6.35629845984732,6.55567657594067,6.75541992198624),.UNSPECIFIED.);
#741=EDGE_CURVE('E273',#282,#273,#740,.T.);
#742=ORIENTED_EDGE('',*,*,#741,.F.);
#743=ORIENTED_EDGE('',*,*,#283,.F.);
#744=EDGE_LOOP('',(#742,#743));
#745=FACE_BOUND('',#744,.T.);
#746=ORIENTED_EDGE('',*,*,#204,.F.);
#747=EDGE_LOOP('',(#746));
#748=FACE_BOUND('',#747,.T.);
#749=ADVANCED_FACE('F222',(#745,#748),#701,.T.);
#750=CARTESIAN_POINT('',(11.2,0.,0.));
#751=DIRECTION('',(1.,0.,0.));
#752=DIRECTION('',(0.,0.,-1.));
#753=AXIS2_PLACEMENT_3D('',#750,#751,#752);
#754=TOROIDAL_SURFACE('',#753,9.455,0.8);
#755=ORIENTED_EDGE('',*,*,#591,.F.);
#756=EDGE_LOOP('',(#755));
#757=FACE_BOUND('',#756,.T.);
#758=ORIENTED_EDGE('',*,*,#608,.F.);
#759=EDGE_LOOP('',(#758));
#760=FACE_BOUND('',#759,.T.);
#761=ADVANCED_FACE('F333',(#757,#760),#754,.F.);
#762=CARTESIAN_POINT('',(7.80000000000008,0.,0.));
#763=DIRECTION('',(-1.,0.,0.));
#764=DIRECTION('',(0.,0.,1.));
#765=AXIS2_PLACEMENT_3D('',#762,#763,#764);
#766=TOROIDAL_SURFACE('',#765,9.455,0.8);
#767=ORIENTED_EDGE('',*,*,#619,.F.);
#768=EDGE_LOOP('',(#767));
#769=FACE_BOUND('',#768,.T.);
#770=ORIENTED_EDGE('',*,*,#647,.F.);
#771=EDGE_LOOP('',(#770));
#772=FACE_BOUND('',#771,.T.);
#773=ADVANCED_FACE('F328',(#769,#772),#766,.F.);
#774=CARTESIAN_POINT('',(6.80000000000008,0.,0.));
#775=DIRECTION('',(-1.,0.,0.));
#776=DIRECTION('',(0.,0.,1.));
#777=AXIS2_PLACEMENT_3D('',#774,#775,#776);
#778=TOROIDAL_SURFACE('',#777,10.675,0.2);
#779=ORIENTED_EDGE('',*,*,#636,.F.);
#780=EDGE_LOOP('',(#779));
#781=FACE_BOUND('',#780,.T.);
#782=ORIENTED_EDGE('',*,*,#148,.F.);
#783=EDGE_LOOP('',(#782));
#784=FACE_BOUND('',#783,.T.);
#785=ADVANCED_FACE('F324',(#781,#784),#778,.T.);
#786=CARTESIAN_POINT('',(12.2,0.,0.));
#787=DIRECTION('',(1.,0.,0.));
#788=DIRECTION('',(0.,0.,-1.));
#789=AXIS2_PLACEMENT_3D('',#786,#787,#788);
#790=TOROIDAL_SURFACE('',#789,10.675,0.2);
#791=ORIENTED_EDGE('',*,*,#475,.F.);
#792=EDGE_LOOP('',(#791));
#793=FACE_BOUND('',#792,.T.);
#794=ORIENTED_EDGE('',*,*,#580,.F.);
#795=EDGE_LOOP('',(#794));
#796=FACE_BOUND('',#795,.T.);
#797=ADVANCED_FACE('F137',(#793,#796),#790,.T.);
#798=CARTESIAN_POINT('',(16.0000000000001,-11.125,-1.02240264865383E-13));
#799=DIRECTION('',(0.,-1.,0.));
#800=DIRECTION('',(0.,0.,-1.));
#801=AXIS2_PLACEMENT_3D('',#798,#799,#800);
#802=CYLINDRICAL_SURFACE('',#801,1.49999999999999);
#803=CARTESIAN_POINT('',(16.,-7.12499999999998,0.));
#804=DIRECTION('',(0.,-1.,0.));
#805=DIRECTION('',(0.,0.,-1.));
#806=AXIS2_PLACEMENT_3D('',#803,#804,#805);
#807=CIRCLE('',#806,1.5);
#808=CARTESIAN_POINT('',(16.,-7.12499999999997,-1.50000000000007));
#809=VERTEX_POINT('',#808);
#810=EDGE_CURVE('E128',#809,#809,#807,.T.);
#811=ORIENTED_EDGE('',*,*,#810,.F.);
#812=EDGE_LOOP('',(#811));
#813=FACE_BOUND('',#812,.T.);
#814=ORIENTED_EDGE('',*,*,#464,.F.);
#815=EDGE_LOOP('',(#814));
#816=FACE_BOUND('',#815,.T.);
#817=ADVANCED_FACE('F132',(#813,#816),#802,.F.);
#818=CARTESIAN_POINT('',(16.,-7.12499999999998,0.));
#819=DIRECTION('',(0.,-1.,0.));
#820=DIRECTION('',(0.,0.,-1.));
#821=AXIS2_PLACEMENT_3D('',#818,#819,#820);
#822=CONICAL_SURFACE('',#821,1.5,1.02974425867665);
#823=CARTESIAN_POINT('',(16.0000000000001,-6.22370907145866,0.));
#824=VERTEX_POINT('',#823);
#825=VERTEX_LOOP('',#824);
#826=FACE_BOUND('',#825,.T.);
#827=ORIENTED_EDGE('',*,*,#810,.T.);
#828=EDGE_LOOP('',(#827));
#829=FACE_BOUND('',#828,.T.);
#830=ADVANCED_FACE('F136',(#826,#829),#822,.F.);
#831=CARTESIAN_POINT('',(27.0000000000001,0.,0.));
#832=DIRECTION('',(-1.,0.,0.));
#833=DIRECTION('',(0.,0.,1.));
#834=AXIS2_PLACEMENT_3D('',#831,#832,#833);
#835=PLANE('',#834);
#836=DIRECTION('',(0.,0.,1.));
#837=VECTOR('',#836,1.);
#838=CARTESIAN_POINT('',(27.0000000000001,-2.19603483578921,11.5));
#839=LINE('',#838,#837);
#840=CARTESIAN_POINT('',(27.0000000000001,-2.19603483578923,5.58367540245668));
#841=VERTEX_POINT('',#840);
#842=EDGE_CURVE('E59',#41,#841,#839,.T.);
#843=ORIENTED_EDGE('',*,*,#842,.F.);
#844=ORIENTED_EDGE('',*,*,#44,.T.);
#845=DIRECTION('',(0.,0.,1.));
#846=VECTOR('',#845,1.);
#847=CARTESIAN_POINT('',(27.,2.19603483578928,11.5));
#848=LINE('',#847,#846);
#849=CARTESIAN_POINT('',(27.0000000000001,2.19603483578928,5.58367540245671));
#850=VERTEX_POINT('',#849);
#851=EDGE_CURVE('E97',#850,#43,#848,.F.);
#852=ORIENTED_EDGE('',*,*,#851,.F.);
#853=CARTESIAN_POINT('',(27.0000000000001,0.,0.));
#854=DIRECTION('',(-1.,0.,0.));
#855=DIRECTION('',(0.,0.,1.));
#856=AXIS2_PLACEMENT_3D('',#853,#854,#855);
#857=CIRCLE('',#856,6.);
#858=EDGE_CURVE('E107',#850,#841,#857,.T.);
#859=ORIENTED_EDGE('',*,*,#858,.T.);
#860=EDGE_LOOP('',(#843,#844,#852,#859));
#861=FACE_BOUND('',#860,.T.);
#862=ADVANCED_FACE('F106',(#861),#835,.T.);
#863=CARTESIAN_POINT('',(27.0000000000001,0.,0.));
#864=DIRECTION('',(-1.,0.,0.));
#865=DIRECTION('',(0.,0.,1.));
#866=AXIS2_PLACEMENT_3D('',#863,#864,#865);
#867=CYLINDRICAL_SURFACE('',#866,6.);
#868=ORIENTED_EDGE('',*,*,#858,.F.);
#869=CARTESIAN_POINT('',(27.0000000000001,2.19603483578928,5.58367540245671));
#870=CARTESIAN_POINT('',(26.9427925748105,2.22208352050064,5.57342795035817));
#871=CARTESIAN_POINT('',(26.8844901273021,2.24593304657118,5.56384073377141));
#872=CARTESIAN_POINT('',(26.7659727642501,2.28906951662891,5.54623360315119));
#873=CARTESIAN_POINT('',(26.7057572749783,2.30835507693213,5.53821416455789));
#874=CARTESIAN_POINT('',(26.522850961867,2.35905870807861,5.51690312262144));
#875=CARTESIAN_POINT('',(26.3977676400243,2.38338428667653,5.50633413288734));
#876=CARTESIAN_POINT('',(26.1446604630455,2.41203518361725,5.49384550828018));
#877=CARTESIAN_POINT('',(26.0166307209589,2.41631618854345,5.49194503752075));
#878=CARTESIAN_POINT('',(25.7617803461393,2.40459392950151,5.49708702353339));
#879=CARTESIAN_POINT('',(25.6349588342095,2.38860676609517,5.50412238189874));
#880=CARTESIAN_POINT('',(25.3888997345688,2.33764240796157,5.52595332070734));
#881=CARTESIAN_POINT('',(25.2695562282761,2.30309525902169,5.54057291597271));
#882=CARTESIAN_POINT('',(25.0382819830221,2.21651362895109,5.57577250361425));
#883=CARTESIAN_POINT('',(24.926356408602,2.1644671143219,5.59635659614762));
#884=CARTESIAN_POINT('',(24.7063265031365,2.04102130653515,5.64258812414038));
#885=CARTESIAN_POINT('',(24.5987837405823,1.96870430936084,5.66845397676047));
#886=CARTESIAN_POINT('',(24.3968329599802,1.80806110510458,5.72171911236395));
#887=CARTESIAN_POINT('',(24.3024285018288,1.7197305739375,5.74911880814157));
#888=CARTESIAN_POINT('',(24.1228882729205,1.52248937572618,5.80458414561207));
#889=CARTESIAN_POINT('',(24.0388059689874,1.41259291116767,5.83257021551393));
#890=CARTESIAN_POINT('',(23.8902742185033,1.17929595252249,5.88417473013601));
#891=CARTESIAN_POINT('',(23.8258234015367,1.05589640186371,5.90779347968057));
#892=CARTESIAN_POINT('',(23.7197382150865,0.801052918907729,5.94765863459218));
#893=CARTESIAN_POINT('',(23.6777288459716,0.669784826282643,5.96402537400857));
#894=CARTESIAN_POINT('',(23.6166244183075,0.401272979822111,5.98808051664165));
#895=CARTESIAN_POINT('',(23.5975169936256,0.264032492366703,5.99577360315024));
#896=CARTESIAN_POINT('',(23.5835601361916,-0.00260848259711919,6.00138189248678));
#897=CARTESIAN_POINT('',(23.5871697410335,-0.131917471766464,5.99991826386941));
#898=CARTESIAN_POINT('',(23.614911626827,-0.387940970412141,5.98881591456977));
#899=CARTESIAN_POINT('',(23.6390424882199,-0.514655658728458,5.97917775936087));
#900=CARTESIAN_POINT('',(23.7062734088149,-0.759783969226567,5.95295564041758));
#901=CARTESIAN_POINT('',(23.7490407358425,-0.878302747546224,5.93649374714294));
#902=CARTESIAN_POINT('',(23.8520253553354,-1.10655404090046,5.89821552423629));
#903=CARTESIAN_POINT('',(23.9122466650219,-1.21628452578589,5.87639796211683));
#904=CARTESIAN_POINT('',(24.0521683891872,-1.43029358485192,5.82811648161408));
#905=CARTESIAN_POINT('',(24.132747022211,-1.53395517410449,5.80146493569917));
#906=CARTESIAN_POINT('',(24.309446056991,-1.72676344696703,5.74702908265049));
#907=CARTESIAN_POINT('',(24.4055735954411,-1.81590342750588,5.7192442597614));
#908=CARTESIAN_POINT('',(24.6170286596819,-1.9821790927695,5.66383935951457));
#909=CARTESIAN_POINT('',(24.7331268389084,-2.05837100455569,5.63631444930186));
#910=CARTESIAN_POINT('',(24.97754721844,-2.1900713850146,5.58646315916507));
#911=CARTESIAN_POINT('',(25.1058657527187,-2.24558603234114,5.56413522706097));
#912=CARTESIAN_POINT('',(25.3675133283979,-2.33259271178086,5.5282170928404));
#913=CARTESIAN_POINT('',(25.5005984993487,-2.36471893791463,5.51439791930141));
#914=CARTESIAN_POINT('',(25.7709350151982,-2.40598463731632,5.49652335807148));
#915=CARTESIAN_POINT('',(25.9081846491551,-2.4151334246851,5.49246401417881));
#916=CARTESIAN_POINT('',(26.1716115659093,-2.41021770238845,5.4946188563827));
#917=CARTESIAN_POINT('',(26.2978331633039,-2.39787437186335,5.50007135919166));
#918=CARTESIAN_POINT('',(26.5461255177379,-2.35375795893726,5.51909331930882));
#919=CARTESIAN_POINT('',(26.6682004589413,-2.3220051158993,5.53265432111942));
#920=CARTESIAN_POINT('',(26.8228699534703,-2.26868736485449,5.55456865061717));
#921=CARTESIAN_POINT('',(26.858870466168,-2.25530197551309,5.56002206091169));
#922=CARTESIAN_POINT('',(26.9300451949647,-2.2268913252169,5.5714622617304));
#923=CARTESIAN_POINT('',(26.9652209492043,-2.21186947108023,5.57744793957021));
#924=CARTESIAN_POINT('',(27.0000000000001,-2.19603483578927,5.58367540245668));
#925=B_SPLINE_CURVE_WITH_KNOTS('',3,(#869,#870,#871,#872,#873,#874,#875,#876,#877,#878,#879,
#880,#881,#882,#883,#884,#885,#886,#887,#888,#889,#890,#891,#892,#893,#894,#895,#896,#897,#898,
#899,#900,#901,#902,#903,#904,#905,#906,#907,#908,#909,#910,#911,#912,#913,#914,#915,#916,#917,
#918,#919,#920,#921,#922,#923,#924),.UNSPECIFIED.,.F.,.F.,(4,2,2,2,2,2,2,2,2,2,2,2,2,2,2,2,2,2,
2,2,2,2,2,2,2,2,2,4),(0.,0.190965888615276,0.381989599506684,0.763598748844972,1.14605114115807,
1.52819991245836,1.90185357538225,2.27576470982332,2.67053658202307,3.06541521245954,
3.48690687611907,3.90836910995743,4.32254896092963,4.736505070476,5.12269845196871,
5.50886512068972,5.88840292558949,6.26802815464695,6.66821030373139,7.06857665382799,
7.49121744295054,7.91373183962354,8.32431305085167,8.73472780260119,9.11376646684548,
9.49241055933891,9.60876083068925,9.72487335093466),.UNSPECIFIED.);
#926=EDGE_CURVE('E94',#850,#841,#925,.T.);
#927=ORIENTED_EDGE('',*,*,#926,.T.);
#928=EDGE_LOOP('',(#868,#927));
#929=FACE_BOUND('',#928,.T.);
#930=ORIENTED_EDGE('',*,*,#176,.T.);
#931=EDGE_LOOP('',(#930));
#932=FACE_BOUND('',#931,.T.);
#933=ADVANCED_FACE('F111',(#929,#932),#867,.F.);
#934=CARTESIAN_POINT('',(26.0000000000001,0.,11.5));
#935=DIRECTION('',(0.,0.,1.));
#936=DIRECTION('',(1.,0.,0.));
#937=AXIS2_PLACEMENT_3D('',#934,#935,#936);
#938=PLANE('',#937);
#939=CARTESIAN_POINT('',(26.0000000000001,0.,11.5));
#940=DIRECTION('',(0.,0.,1.));
#941=DIRECTION('',(1.,0.,0.));
#942=AXIS2_PLACEMENT_3D('',#939,#940,#941);
#943=CIRCLE('',#942,2.413);
#944=CARTESIAN_POINT('',(28.4130000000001,0.,11.5));
#945=VERTEX_POINT('',#944);
#946=EDGE_CURVE('E102',#945,#945,#943,.T.);
#947=ORIENTED_EDGE('',*,*,#946,.F.);
#948=EDGE_LOOP('',(#947));
#949=FACE_BOUND('',#948,.T.);
#950=ORIENTED_EDGE('',*,*,#225,.T.);
#951=CARTESIAN_POINT('',(26.0000000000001,0.,11.5));
#952=DIRECTION('',(0.,0.,1.));
#953=DIRECTION('',(1.,0.,0.));
#954=AXIS2_PLACEMENT_3D('',#951,#952,#953);
#955=CIRCLE('',#954,5.5);
#956=EDGE_CURVE('E288',#224,#294,#955,.T.);
#957=ORIENTED_EDGE('',*,*,#956,.T.);
#958=ORIENTED_EDGE('',*,*,#295,.T.);
#959=EDGE_CURVE('E165',#286,#222,#955,.T.);
#960=ORIENTED_EDGE('',*,*,#959,.T.);
#961=EDGE_LOOP('',(#950,#957,#958,#960));
#962=FACE_BOUND('',#961,.T.);
#963=ADVANCED_FACE('F145',(#949,#962),#938,.T.);
#964=CARTESIAN_POINT('',(26.0000000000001,0.,11.5));
#965=DIRECTION('',(0.,0.,1.));
#966=DIRECTION('',(1.,0.,0.));
#967=AXIS2_PLACEMENT_3D('',#964,#965,#966);
#968=CYLINDRICAL_SURFACE('',#967,5.5);
#969=ORIENTED_EDGE('',*,*,#956,.F.);
#970=ORIENTED_EDGE('',*,*,#342,.F.);
#971=EDGE_LOOP('',(#969,#970));
#972=FACE_BOUND('',#971,.T.);
#973=ADVANCED_FACE('F278',(#972),#968,.F.);
#974=ORIENTED_EDGE('',*,*,#959,.F.);
#975=ORIENTED_EDGE('',*,*,#287,.F.);
#976=ORIENTED_EDGE('',*,*,#741,.T.);
#977=ORIENTED_EDGE('',*,*,#274,.F.);
#978=EDGE_LOOP('',(#974,#975,#976,#977));
#979=FACE_BOUND('',#978,.T.);
#980=ADVANCED_FACE('F156',(#979),#968,.F.);
#981=CARTESIAN_POINT('',(26.0000000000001,0.,11.5));
#982=DIRECTION('',(0.,0.,1.));
#983=DIRECTION('',(1.,0.,0.));
#984=AXIS2_PLACEMENT_3D('',#981,#982,#983);
#985=CYLINDRICAL_SURFACE('',#984,2.413);
#986=ORIENTED_EDGE('',*,*,#946,.T.);
#987=EDGE_LOOP('',(#986));
#988=FACE_BOUND('',#987,.T.);
#989=ORIENTED_EDGE('',*,*,#842,.T.);
#990=ORIENTED_EDGE('',*,*,#926,.F.);
#991=ORIENTED_EDGE('',*,*,#851,.T.);
#992=ORIENTED_EDGE('',*,*,#131,.F.);
#993=EDGE_LOOP('',(#989,#990,#991,#992));
#994=FACE_BOUND('',#993,.T.);
#995=ADVANCED_FACE('F96',(#988,#994),#985,.F.);
#996=CLOSED_SHELL('',(#135,#163,#191,#211,#357,#377,#567,#595,#623,#651,#663,#683,#696,#749,
#761,#773,#785,#797,#817,#830,#862,#933,#963,#973,#980,#995));
#997=MANIFOLD_SOLID_BREP('B2',#996);
#998=ADVANCED_BREP_SHAPE_REPRESENTATION('',(#18,#997),#14);
#999=SHAPE_DEFINITION_REPRESENTATION(#9,#998);
ENDSEC;
END-ISO-10303-21;
